One B-rep face of a CAD part: STEP entity #251.
In plain terms, the planar face has unit normal (0, 0, -1).
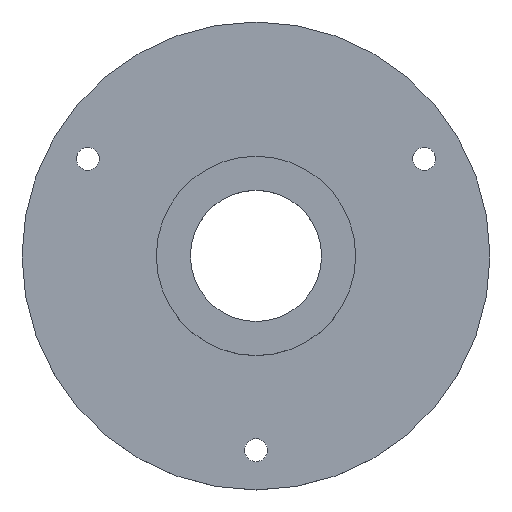
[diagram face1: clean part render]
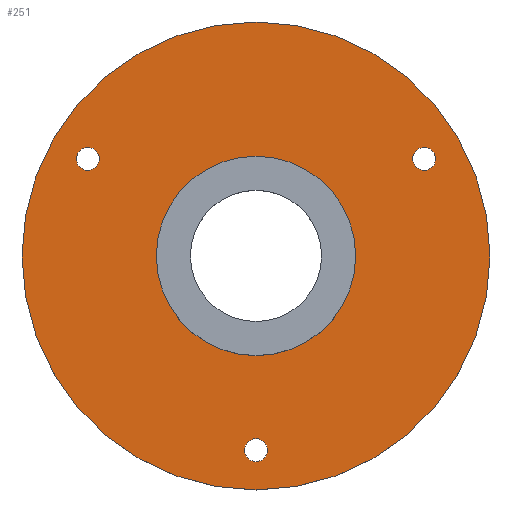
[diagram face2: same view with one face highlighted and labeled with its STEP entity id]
Its self-contained STEP definition (entity closure, numbers rounded to 3 decimals):
#49 = CYLINDRICAL_SURFACE('',#50,22.3);
#50 = AXIS2_PLACEMENT_3D('',#51,#52,#53);
#51 = CARTESIAN_POINT('',(0.,0.,-5.));
#52 = DIRECTION('',(0.,0.,1.));
#53 = DIRECTION('',(1.,0.,-0.));
#74 = VERTEX_POINT('',#75);
#75 = CARTESIAN_POINT('',(22.3,0.,-5.));
#96 = EDGE_CURVE('',#74,#74,#97,.T.);
#97 = SURFACE_CURVE('',#98,(#103,#110),.PCURVE_S1.);
#98 = CIRCLE('',#99,22.3);
#99 = AXIS2_PLACEMENT_3D('',#100,#101,#102);
#100 = CARTESIAN_POINT('',(0.,0.,-5.));
#101 = DIRECTION('',(0.,0.,1.));
#102 = DIRECTION('',(1.,0.,-0.));
#103 = PCURVE('',#49,#104);
#104 = DEFINITIONAL_REPRESENTATION('',(#105),#109);
#105 = LINE('',#106,#107);
#106 = CARTESIAN_POINT('',(0.,0.));
#107 = VECTOR('',#108,1.);
#108 = DIRECTION('',(1.,0.));
#109 = ( GEOMETRIC_REPRESENTATION_CONTEXT(2) 
PARAMETRIC_REPRESENTATION_CONTEXT() REPRESENTATION_CONTEXT('2D SPACE',''
  ) );
#110 = PCURVE('',#111,#116);
#111 = PLANE('',#112);
#112 = AXIS2_PLACEMENT_3D('',#113,#114,#115);
#113 = CARTESIAN_POINT('',(0.,0.,-5.));
#114 = DIRECTION('',(0.,0.,1.));
#115 = DIRECTION('',(1.,0.,-0.));
#116 = DEFINITIONAL_REPRESENTATION('',(#117),#121);
#117 = CIRCLE('',#118,22.3);
#118 = AXIS2_PLACEMENT_2D('',#119,#120);
#119 = CARTESIAN_POINT('',(0.,0.));
#120 = DIRECTION('',(1.,0.));
#121 = ( GEOMETRIC_REPRESENTATION_CONTEXT(2) 
PARAMETRIC_REPRESENTATION_CONTEXT() REPRESENTATION_CONTEXT('2D SPACE',''
  ) );
#147 = CYLINDRICAL_SURFACE('',#148,1.1);
#148 = AXIS2_PLACEMENT_3D('',#149,#150,#151);
#149 = CARTESIAN_POINT('',(0.,-18.5,-11.));
#150 = DIRECTION('',(0.,0.,1.));
#151 = DIRECTION('',(1.,0.,-0.));
#178 = CYLINDRICAL_SURFACE('',#179,1.1);
#179 = AXIS2_PLACEMENT_3D('',#180,#181,#182);
#180 = CARTESIAN_POINT('',(-16.021,9.25,-11.));
#181 = DIRECTION('',(0.,0.,1.));
#182 = DIRECTION('',(1.,0.,-0.));
#240 = CYLINDRICAL_SURFACE('',#241,1.1);
#241 = AXIS2_PLACEMENT_3D('',#242,#243,#244);
#242 = CARTESIAN_POINT('',(16.021,9.25,-11.));
#243 = DIRECTION('',(0.,0.,1.));
#244 = DIRECTION('',(1.,0.,-0.));
#251 = ADVANCED_FACE('',(#252,#255,#281,#307,#338),#111,.F.);
#252 = FACE_BOUND('',#253,.F.);
#253 = EDGE_LOOP('',(#254));
#254 = ORIENTED_EDGE('',*,*,#96,.T.);
#255 = FACE_BOUND('',#256,.F.);
#256 = EDGE_LOOP('',(#257));
#257 = ORIENTED_EDGE('',*,*,#258,.F.);
#258 = EDGE_CURVE('',#259,#259,#261,.T.);
#259 = VERTEX_POINT('',#260);
#260 = CARTESIAN_POINT('',(1.1,-18.5,-5.));
#261 = SURFACE_CURVE('',#262,(#267,#274),.PCURVE_S1.);
#262 = CIRCLE('',#263,1.1);
#263 = AXIS2_PLACEMENT_3D('',#264,#265,#266);
#264 = CARTESIAN_POINT('',(0.,-18.5,-5.));
#265 = DIRECTION('',(0.,0.,1.));
#266 = DIRECTION('',(1.,0.,-0.));
#267 = PCURVE('',#111,#268);
#268 = DEFINITIONAL_REPRESENTATION('',(#269),#273);
#269 = CIRCLE('',#270,1.1);
#270 = AXIS2_PLACEMENT_2D('',#271,#272);
#271 = CARTESIAN_POINT('',(0.,-18.5));
#272 = DIRECTION('',(1.,0.));
#273 = ( GEOMETRIC_REPRESENTATION_CONTEXT(2) 
PARAMETRIC_REPRESENTATION_CONTEXT() REPRESENTATION_CONTEXT('2D SPACE',''
  ) );
#274 = PCURVE('',#147,#275);
#275 = DEFINITIONAL_REPRESENTATION('',(#276),#280);
#276 = LINE('',#277,#278);
#277 = CARTESIAN_POINT('',(0.,6.));
#278 = VECTOR('',#279,1.);
#279 = DIRECTION('',(1.,0.));
#280 = ( GEOMETRIC_REPRESENTATION_CONTEXT(2) 
PARAMETRIC_REPRESENTATION_CONTEXT() REPRESENTATION_CONTEXT('2D SPACE',''
  ) );
#281 = FACE_BOUND('',#282,.F.);
#282 = EDGE_LOOP('',(#283));
#283 = ORIENTED_EDGE('',*,*,#284,.F.);
#284 = EDGE_CURVE('',#285,#285,#287,.T.);
#285 = VERTEX_POINT('',#286);
#286 = CARTESIAN_POINT('',(-14.921,9.25,-5.));
#287 = SURFACE_CURVE('',#288,(#293,#300),.PCURVE_S1.);
#288 = CIRCLE('',#289,1.1);
#289 = AXIS2_PLACEMENT_3D('',#290,#291,#292);
#290 = CARTESIAN_POINT('',(-16.021,9.25,-5.));
#291 = DIRECTION('',(0.,0.,1.));
#292 = DIRECTION('',(1.,0.,-0.));
#293 = PCURVE('',#111,#294);
#294 = DEFINITIONAL_REPRESENTATION('',(#295),#299);
#295 = CIRCLE('',#296,1.1);
#296 = AXIS2_PLACEMENT_2D('',#297,#298);
#297 = CARTESIAN_POINT('',(-16.021,9.25));
#298 = DIRECTION('',(1.,0.));
#299 = ( GEOMETRIC_REPRESENTATION_CONTEXT(2) 
PARAMETRIC_REPRESENTATION_CONTEXT() REPRESENTATION_CONTEXT('2D SPACE',''
  ) );
#300 = PCURVE('',#178,#301);
#301 = DEFINITIONAL_REPRESENTATION('',(#302),#306);
#302 = LINE('',#303,#304);
#303 = CARTESIAN_POINT('',(0.,6.));
#304 = VECTOR('',#305,1.);
#305 = DIRECTION('',(1.,0.));
#306 = ( GEOMETRIC_REPRESENTATION_CONTEXT(2) 
PARAMETRIC_REPRESENTATION_CONTEXT() REPRESENTATION_CONTEXT('2D SPACE',''
  ) );
#307 = FACE_BOUND('',#308,.F.);
#308 = EDGE_LOOP('',(#309));
#309 = ORIENTED_EDGE('',*,*,#310,.F.);
#310 = EDGE_CURVE('',#311,#311,#313,.T.);
#311 = VERTEX_POINT('',#312);
#312 = CARTESIAN_POINT('',(9.5,0.,-5.));
#313 = SURFACE_CURVE('',#314,(#319,#326),.PCURVE_S1.);
#314 = CIRCLE('',#315,9.5);
#315 = AXIS2_PLACEMENT_3D('',#316,#317,#318);
#316 = CARTESIAN_POINT('',(0.,0.,-5.));
#317 = DIRECTION('',(0.,0.,1.));
#318 = DIRECTION('',(1.,0.,-0.));
#319 = PCURVE('',#111,#320);
#320 = DEFINITIONAL_REPRESENTATION('',(#321),#325);
#321 = CIRCLE('',#322,9.5);
#322 = AXIS2_PLACEMENT_2D('',#323,#324);
#323 = CARTESIAN_POINT('',(0.,0.));
#324 = DIRECTION('',(1.,0.));
#325 = ( GEOMETRIC_REPRESENTATION_CONTEXT(2) 
PARAMETRIC_REPRESENTATION_CONTEXT() REPRESENTATION_CONTEXT('2D SPACE',''
  ) );
#326 = PCURVE('',#327,#332);
#327 = CYLINDRICAL_SURFACE('',#328,9.5);
#328 = AXIS2_PLACEMENT_3D('',#329,#330,#331);
#329 = CARTESIAN_POINT('',(0.,0.,-9.));
#330 = DIRECTION('',(0.,0.,1.));
#331 = DIRECTION('',(1.,0.,-0.));
#332 = DEFINITIONAL_REPRESENTATION('',(#333),#337);
#333 = LINE('',#334,#335);
#334 = CARTESIAN_POINT('',(0.,4.));
#335 = VECTOR('',#336,1.);
#336 = DIRECTION('',(1.,0.));
#337 = ( GEOMETRIC_REPRESENTATION_CONTEXT(2) 
PARAMETRIC_REPRESENTATION_CONTEXT() REPRESENTATION_CONTEXT('2D SPACE',''
  ) );
#338 = FACE_BOUND('',#339,.F.);
#339 = EDGE_LOOP('',(#340));
#340 = ORIENTED_EDGE('',*,*,#341,.F.);
#341 = EDGE_CURVE('',#342,#342,#344,.T.);
#342 = VERTEX_POINT('',#343);
#343 = CARTESIAN_POINT('',(17.121,9.25,-5.));
#344 = SURFACE_CURVE('',#345,(#350,#357),.PCURVE_S1.);
#345 = CIRCLE('',#346,1.1);
#346 = AXIS2_PLACEMENT_3D('',#347,#348,#349);
#347 = CARTESIAN_POINT('',(16.021,9.25,-5.));
#348 = DIRECTION('',(0.,0.,1.));
#349 = DIRECTION('',(1.,0.,-0.));
#350 = PCURVE('',#111,#351);
#351 = DEFINITIONAL_REPRESENTATION('',(#352),#356);
#352 = CIRCLE('',#353,1.1);
#353 = AXIS2_PLACEMENT_2D('',#354,#355);
#354 = CARTESIAN_POINT('',(16.021,9.25));
#355 = DIRECTION('',(1.,0.));
#356 = ( GEOMETRIC_REPRESENTATION_CONTEXT(2) 
PARAMETRIC_REPRESENTATION_CONTEXT() REPRESENTATION_CONTEXT('2D SPACE',''
  ) );
#357 = PCURVE('',#240,#358);
#358 = DEFINITIONAL_REPRESENTATION('',(#359),#363);
#359 = LINE('',#360,#361);
#360 = CARTESIAN_POINT('',(0.,6.));
#361 = VECTOR('',#362,1.);
#362 = DIRECTION('',(1.,0.));
#363 = ( GEOMETRIC_REPRESENTATION_CONTEXT(2) 
PARAMETRIC_REPRESENTATION_CONTEXT() REPRESENTATION_CONTEXT('2D SPACE',''
  ) );
